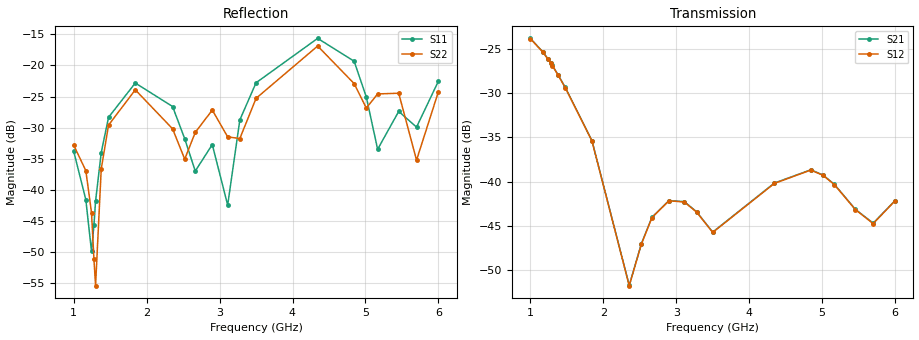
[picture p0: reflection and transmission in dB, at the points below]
!Agilent Technologies,E8364B,MY43040528,A.07.50.67
!Agilent E8364B: A.07.50.67
!Date: Sunday, March 01, 2026 22:40:29
!Correction: S11(Full 2 Port(1,2))
!S21(Full 2 Port(1,2))
!S12(Full 2 Port(1,2))
!S22(Full 2 Port(1,2))
!S2P File: Measurements: S11, S21, S12, S22:
# Hz S  dB  R 50
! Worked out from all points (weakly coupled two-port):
!   451 points, 1 GHz to 6 GHz, reference 50 ohm
!   highest |S21| = -23.80 dB at 1 GHz (marker M1); lowest = -51.7 dB at 2.356 GHz (marker M2)
!   lowest |S11| = -49.9 dB at 1.244 GHz (marker M3), VSWR 1.01, Z = 50.2 - j0.277 ohm
!   |S11| at or under -10 dB: start of sweep to end of sweep
!   |S22| runs from -55.4 to -16.9 dB; largest |S21 - S12| = 0.00025
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1e9  -33.77 14.6  -23.80 155.2  -23.83 155.2  -32.79 -13.0
1.166667e9  -41.56 1.8  -25.29 60.2  -25.32 60.2  -36.89 -20.1
1.244444e9  -49.87 -59.3  -26.14 16.0  -26.18 16.1  -43.64 -42.1
1.277778e9  -45.63 -123.9  -26.55 -2.8  -26.58 -2.7  -51.11 -72.6
1.3e9  -41.80 -141.5  -26.83 -15.3  -26.87 -15.2  -55.36 -163.1
1.377778e9  -33.98 -173.7  -27.89 -58.5  -27.92 -58.5  -36.61 117.7
1.477778e9  -28.33 155.3  -29.34 -113.1  -29.37 -113.1  -29.58 85.9
1.844444e9  -22.82 75.1  -35.37 51.6  -35.39 51.7  -23.91 -8.9
2.355556e9  -26.59 0.3  -51.73 -148.5  -51.76 -148.6  -30.17 -93.9
2.522222e9  -31.77 -17.6  -47.02 172.3  -47.05 172.4  -35.04 -81.1
2.666667e9  -36.96 16.3  -44.03 104.5  -44.07 104.7  -30.75 -64.3
2.9e9  -32.70 20.7  -42.14 -15.6  -42.16 -15.5  -27.16 -109.0
3.111111e9  -42.43 58.8  -42.26 -126.0  -42.30 -126.1  -31.47 -142.1
3.277778e9  -28.74 91.4  -43.40 149.3  -43.43 149.4  -31.73 -109.2
3.5e9  -22.78 55.2  -45.70 47.4  -45.74 47.5  -25.28 -130.2
4.344444e9  -15.65 -47.4  -40.16 24.5  -40.20 24.6  -16.88 111.4
4.844444e9  -19.32 -133.0  -38.66 105.2  -38.69 105.2  -22.91 24.4
5.011111e9  -25.05 -156.8  -39.24 7.3  -39.28 7.3  -26.84 30.1
5.166667e9  -33.46 -125.0  -40.29 -86.1  -40.33 -86.1  -24.57 34.3
5.455556e9  -27.38 -106.9  -43.13 89.7  -43.16 89.7  -24.46 -20.8
5.7e9  -29.90 -87.7  -44.69 -86.5  -44.74 -86.5  -35.20 -13.7
6e9  -22.51 -82.8  -42.13 61.2  -42.16 61.1  -24.21 -4.1
